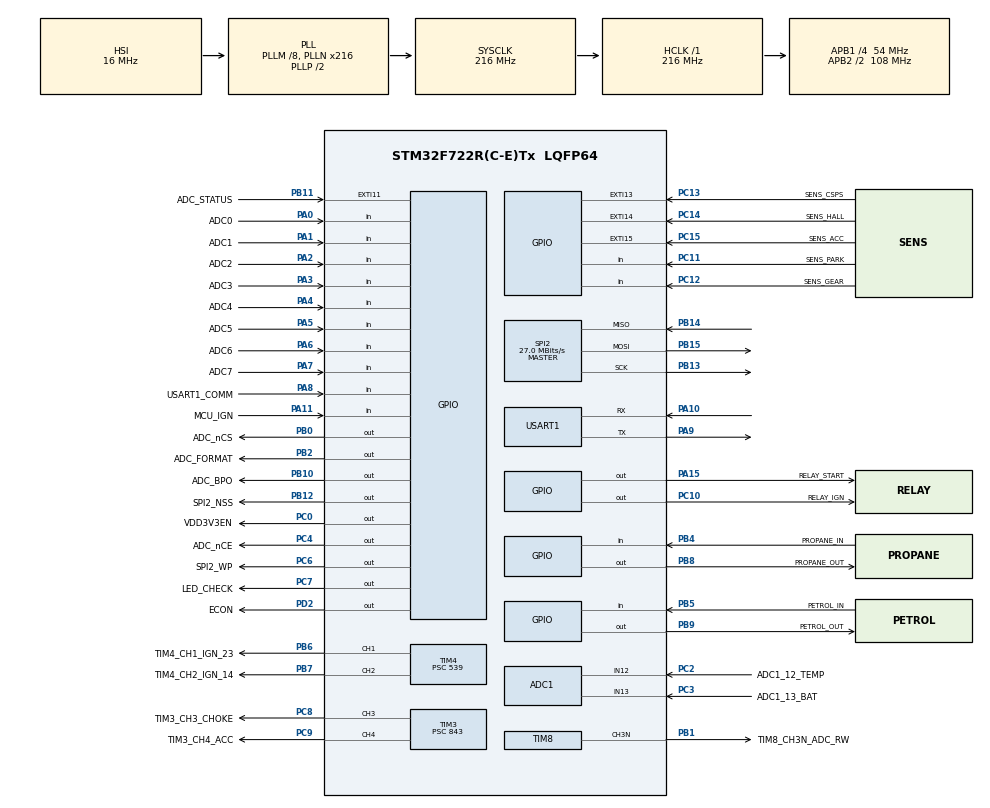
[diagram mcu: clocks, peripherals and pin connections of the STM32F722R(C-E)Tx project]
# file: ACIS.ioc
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ADC1.Channel-0\#ChannelRegularConversion=ADC_CHANNEL_12
ADC1.Channel-1\#ChannelRegularConversion=ADC_CHANNEL_13
ADC1.DMAContinuousRequests=ENABLE
ADC1.DataAlign=ADC_DATAALIGN_LEFT
ADC1.ExternalTrigConv=ADC_EXTERNALTRIGCONV_T8_TRGO
ADC1.NbrOfConversion=2
ADC1.NbrOfConversionFlag=1
ADC1.Rank-0\#ChannelRegularConversion=1
ADC1.Rank-1\#ChannelRegularConversion=2
ADC1.SamplingTime-0\#ChannelRegularConversion=ADC_SAMPLETIME_3CYCLES
ADC1.SamplingTime-1\#ChannelRegularConversion=ADC_SAMPLETIME_3CYCLES
ADC1.ScanConvMode=ADC_SCAN_ENABLE
ADC1.master=1
CORTEX_M7.ART_ACCLERATOR_ENABLE=1
CORTEX_M7.CPU_DCache=Enabled
CORTEX_M7.CPU_ICache=Enabled
CORTEX_M7.FlashInterface=TCM_Enabled
CORTEX_M7.PREFETCH_ENABLE=1
CRC.CRCLength=CRC_POLYLENGTH_16B
CRC.DefaultInitValueUse=DEFAULT_INIT_VALUE_DISABLE
CRC.DefaultPolynomialUse=DEFAULT_POLYNOMIAL_DISABLE
CRC.InputDataInversionMode=CRC_INPUTDATA_INVERSION_BYTE
CRC.OutputDataInversionMode=CRC_OUTPUTDATA_INVERSION_ENABLE
Dma.ADC1.2.Direction=DMA_PERIPH_TO_MEMORY
Dma.ADC1.2.FIFOMode=DMA_FIFOMODE_DISABLE
Dma.ADC1.2.Instance=DMA2_Stream0
Dma.ADC1.2.MemDataAlignment=DMA_MDATAALIGN_HALFWORD
Dma.ADC1.2.MemInc=DMA_MINC_ENABLE
Dma.ADC1.2.Mode=DMA_CIRCULAR
Dma.ADC1.2.PeriphDataAlignment=DMA_PDATAALIGN_HALFWORD
Dma.ADC1.2.PeriphInc=DMA_PINC_DISABLE
Dma.ADC1.2.Priority=DMA_PRIORITY_LOW
Dma.Request0=USART1_RX
Dma.Request1=USART1_TX
Dma.Request2=ADC1
Dma.Request3=TIM7_UP
Dma.Request4=SPI2_TX
Dma.Request5=SPI2_RX
Dma.SPI2_RX.5.Direction=DMA_PERIPH_TO_MEMORY
Dma.SPI2_RX.5.FIFOMode=DMA_FIFOMODE_DISABLE
Dma.SPI2_RX.5.Instance=DMA1_Stream3
Dma.SPI2_RX.5.MemDataAlignment=DMA_MDATAALIGN_BYTE
Dma.SPI2_RX.5.MemInc=DMA_MINC_ENABLE
Dma.SPI2_RX.5.Mode=DMA_NORMAL
Dma.SPI2_RX.5.PeriphDataAlignment=DMA_PDATAALIGN_BYTE
Dma.SPI2_RX.5.PeriphInc=DMA_PINC_DISABLE
Dma.SPI2_RX.5.Priority=DMA_PRIORITY_LOW
Dma.SPI2_TX.4.Direction=DMA_MEMORY_TO_PERIPH
Dma.SPI2_TX.4.FIFOMode=DMA_FIFOMODE_DISABLE
Dma.SPI2_TX.4.Instance=DMA1_Stream4
Dma.SPI2_TX.4.MemDataAlignment=DMA_MDATAALIGN_BYTE
Dma.SPI2_TX.4.MemInc=DMA_MINC_ENABLE
Dma.SPI2_TX.4.Mode=DMA_NORMAL
Dma.SPI2_TX.4.PeriphDataAlignment=DMA_PDATAALIGN_BYTE
Dma.SPI2_TX.4.PeriphInc=DMA_PINC_DISABLE
Dma.SPI2_TX.4.Priority=DMA_PRIORITY_LOW
Dma.TIM7_UP.3.Direction=DMA_PERIPH_TO_MEMORY
Dma.TIM7_UP.3.FIFOMode=DMA_FIFOMODE_DISABLE
Dma.TIM7_UP.3.Instance=DMA1_Stream2
Dma.TIM7_UP.3.MemDataAlignment=DMA_MDATAALIGN_BYTE
Dma.TIM7_UP.3.MemInc=DMA_MINC_ENABLE
Dma.TIM7_UP.3.Mode=DMA_CIRCULAR
Dma.TIM7_UP.3.PeriphDataAlignment=DMA_PDATAALIGN_BYTE
Dma.TIM7_UP.3.PeriphInc=DMA_PINC_DISABLE
Dma.TIM7_UP.3.Priority=DMA_PRIORITY_LOW
Dma.USART1_RX.0.Direction=DMA_PERIPH_TO_MEMORY
Dma.USART1_RX.0.FIFOMode=DMA_FIFOMODE_DISABLE
Dma.USART1_RX.0.Instance=DMA2_Stream2
Dma.USART1_RX.0.MemDataAlignment=DMA_MDATAALIGN_BYTE
Dma.USART1_RX.0.MemInc=DMA_MINC_ENABLE
Dma.USART1_RX.0.Mode=DMA_NORMAL
Dma.USART1_RX.0.PeriphDataAlignment=DMA_PDATAALIGN_BYTE
Dma.USART1_RX.0.PeriphInc=DMA_PINC_DISABLE
Dma.USART1_RX.0.Priority=DMA_PRIORITY_LOW
Dma.USART1_TX.1.Direction=DMA_MEMORY_TO_PERIPH
Dma.USART1_TX.1.FIFOMode=DMA_FIFOMODE_DISABLE
Dma.USART1_TX.1.Instance=DMA2_Stream7
Dma.USART1_TX.1.MemDataAlignment=DMA_MDATAALIGN_BYTE
Dma.USART1_TX.1.MemInc=DMA_MINC_ENABLE
Dma.USART1_TX.1.Mode=DMA_NORMAL
Dma.USART1_TX.1.PeriphDataAlignment=DMA_PDATAALIGN_BYTE
Dma.USART1_TX.1.PeriphInc=DMA_PINC_DISABLE
Dma.USART1_TX.1.Priority=DMA_PRIORITY_LOW
Mcu.Family=STM32F7
Mcu.Name=STM32F722R(C-E)Tx
Mcu.Package=LQFP64
NVIC.DMA1_Stream2_IRQn=true\:0\:0\:false\:false\:true\:false\:true
NVIC.DMA1_Stream3_IRQn=true\:0\:0\:false\:false\:true\:false\:true
NVIC.DMA1_Stream4_IRQn=true\:0\:0\:false\:false\:true\:false\:true
NVIC.DMA2_Stream0_IRQn=true\:0\:0\:false\:false\:true\:false\:true
NVIC.DMA2_Stream2_IRQn=true\:0\:0\:false\:false\:true\:false\:true
NVIC.DMA2_Stream7_IRQn=true\:0\:0\:false\:false\:true\:false\:true
NVIC.EXTI15_10_IRQn=true\:0\:0\:false\:false\:true\:true\:true
NVIC.PriorityGroup=NVIC_PRIORITYGROUP_4
NVIC.SPI2_IRQn=true\:0\:0\:false\:false\:true\:true\:true
NVIC.TIM7_IRQn=true\:0\:0\:false\:false\:true\:true\:true
NVIC.USART1_IRQn=true\:0\:0\:false\:false\:true\:true\:true
PA0-WKUP.GPIO_Label=ADC0
PA0-WKUP.GPIO_PuPd=GPIO_PULLDOWN
PA0-WKUP.Signal=GPIO_Input
PA1.GPIO_Label=ADC1
PA1.GPIO_PuPd=GPIO_PULLDOWN
PA1.Signal=GPIO_Input
PA10.GPIO_PuPd=GPIO_PULLUP
PA10.Mode=Asynchronous
PA10.Signal=USART1_RX
PA11.GPIO_Label=MCU_IGN
PA11.Signal=GPIO_Input
PA13.Mode=Trace_Asynchronous_SW
PA13.Signal=SYS_JTMS-SWDIO
PA14.Mode=Trace_Asynchronous_SW
PA14.Signal=SYS_JTCK-SWCLK
PA15.GPIO_Label=RELAY_START
PA15.Signal=GPIO_Output
PA2.GPIO_Label=ADC2
PA2.GPIO_PuPd=GPIO_PULLDOWN
PA2.Signal=GPIO_Input
PA3.GPIO_Label=ADC3
PA3.GPIO_PuPd=GPIO_PULLDOWN
PA3.Signal=GPIO_Input
PA4.GPIO_Label=ADC4
PA4.GPIO_PuPd=GPIO_PULLDOWN
PA4.Signal=GPIO_Input
PA5.GPIO_Label=ADC5
PA5.GPIO_PuPd=GPIO_PULLDOWN
PA5.Signal=GPIO_Input
PA6.GPIO_Label=ADC6
PA6.GPIO_PuPd=GPIO_PULLDOWN
PA6.Signal=GPIO_Input
PA7.GPIO_Label=ADC7
PA7.GPIO_PuPd=GPIO_PULLDOWN
PA7.Signal=GPIO_Input
PA8.GPIO_Label=USART1_COMM
PA8.Signal=GPIO_Input
PA9.GPIO_PuPd=GPIO_PULLUP
PA9.Mode=Asynchronous
PA9.Signal=USART1_TX
PB0.GPIO_Label=ADC_nCS
PB0.PinState=GPIO_PIN_SET
PB0.Signal=GPIO_Output
PB1.GPIO_Label=TIM8_CH3N_ADC_RW
PB1.GPIO_PuPd=GPIO_NOPULL
PB1.GPIO_Speed=GPIO_SPEED_FREQ_VERY_HIGH
PB1.Mode=PWM Generation3 CH3N
PB1.Signal=TIM8_CH3N
PB10.GPIO_Label=ADC_BPO
PB10.Signal=GPIO_Output
PB11.GPIO_Label=ADC_STATUS
PB11.GPIO_ModeDefaultEXTI=GPIO_MODE_IT_FALLING
PB11.GPIO_PuPd=GPIO_NOPULL
PB11.Signal=GPXTI11
PB12.GPIO_Label=SPI2_NSS
PB12.GPIO_Speed=GPIO_SPEED_FREQ_VERY_HIGH
PB12.Signal=GPIO_Output
PB13.GPIO_PuPd=GPIO_PULLUP
PB13.Mode=Full_Duplex_Master
PB13.Signal=SPI2_SCK
PB14.GPIO_PuPd=GPIO_PULLUP
PB14.Mode=Full_Duplex_Master
PB14.Signal=SPI2_MISO
PB15.GPIO_PuPd=GPIO_PULLUP
PB15.Mode=Full_Duplex_Master
PB15.Signal=SPI2_MOSI
PB2.GPIO_Label=ADC_FORMAT
PB2.Signal=GPIO_Output
PB3.Mode=Trace_Asynchronous_SW
PB3.Signal=SYS_JTDO-SWO
PB4.GPIO_Label=PROPANE_IN
PB4.Signal=GPIO_Input
PB5.GPIO_Label=PETROL_IN
PB5.Signal=GPIO_Input
PB6.GPIO_Label=TIM4_CH1_IGN_23
PB6.GPIO_PuPd=GPIO_NOPULL
PB6.GPIO_Speed=GPIO_SPEED_FREQ_VERY_HIGH
PB6.Signal=S_TIM4_CH1
PB7.GPIO_Label=TIM4_CH2_IGN_14
PB7.GPIO_PuPd=GPIO_NOPULL
PB7.GPIO_Speed=GPIO_SPEED_FREQ_VERY_HIGH
PB7.Signal=S_TIM4_CH2
PB8.GPIO_Label=PROPANE_OUT
PB8.Signal=GPIO_Output
PB9.GPIO_Label=PETROL_OUT
PB9.Signal=GPIO_Output
PC0.GPIO_Label=VDD3V3EN
PC0.Signal=GPIO_Output
PC10.GPIO_Label=RELAY_IGN
PC10.Signal=GPIO_Output
PC11.GPIO_Label=SENS_PARK
PC11.Signal=GPIO_Input
PC12.GPIO_Label=SENS_GEAR
PC12.Signal=GPIO_Input
PC13.GPIO_Label=SENS_CSPS
PC13.GPIO_ModeDefaultEXTI=GPIO_MODE_IT_RISING_FALLING
PC13.Signal=GPXTI13
PC14-OSC32_IN.GPIO_Label=SENS_HALL
PC14-OSC32_IN.GPIO_ModeDefaultEXTI=GPIO_MODE_IT_RISING
PC14-OSC32_IN.Signal=GPXTI14
PC15-OSC32_OUT.GPIO_Label=SENS_ACC
PC15-OSC32_OUT.Signal=GPXTI15
PC2.GPIO_Label=ADC1_12_TEMP
PC2.Signal=ADCx_IN12
PC3.GPIO_Label=ADC1_13_BAT
PC3.Signal=ADCx_IN13
PC4.GPIO_Label=ADC_nCE
PC4.PinState=GPIO_PIN_SET
PC4.Signal=GPIO_Output
PC6.GPIO_Label=SPI2_WP
PC6.GPIO_Speed=GPIO_SPEED_FREQ_VERY_HIGH
PC6.Signal=GPIO_Output
PC7.GPIO_Label=LED_CHECK
PC7.PinState=GPIO_PIN_SET
PC7.Signal=GPIO_Output
PC8.GPIO_Label=TIM3_CH3_CHOKE
PC8.GPIO_PuPd=GPIO_NOPULL
PC8.GPIO_Speed=GPIO_SPEED_FREQ_VERY_HIGH
PC8.Signal=S_TIM3_CH3
PC9.GPIO_Label=TIM3_CH4_ACC
PC9.GPIO_PuPd=GPIO_NOPULL
PC9.GPIO_Speed=GPIO_SPEED_FREQ_VERY_HIGH
PC9.Signal=S_TIM3_CH4
PD2.GPIO_Label=ECON
PD2.Signal=GPIO_Output
ProjectManager.HeapSize=0x200
ProjectManager.StackSize=0x400
ProjectManager.TargetToolchain=STM32CubeIDE
RCC.AHBFreq_Value=216000000
RCC.APB1CLKDivider=RCC_HCLK_DIV4
RCC.APB1Freq_Value=54000000
RCC.APB1TimFreq_Value=108000000
RCC.APB2CLKDivider=RCC_HCLK_DIV2
RCC.APB2Freq_Value=108000000
RCC.APB2TimFreq_Value=216000000
RCC.CortexFreq_Value=216000000
RCC.HCLKFreq_Value=216000000
RCC.HSE_VALUE=25000000
RCC.HSI_VALUE=16000000
RCC.LSE_VALUE=32768
RCC.PLLM=8
RCC.PLLN=216
RCC.PLLQ=9
RCC.SYSCLKFreq_VALUE=216000000
RCC.SYSCLKSource=RCC_SYSCLKSOURCE_PLLCLK
RCC.USBFreq_Value=48000000
RCC.VCOOutputFreq_Value=432000000
SH.ADCx_IN12.0=ADC1_IN12,IN12
SH.ADCx_IN13.0=ADC1_IN13,IN13
SH.S_TIM3_CH3.0=TIM3_CH3,PWM Generation3 CH3
SH.S_TIM3_CH4.0=TIM3_CH4,PWM Generation4 CH4
SH.S_TIM4_CH1.0=TIM4_CH1,PWM Generation1 CH1
SH.S_TIM4_CH2.0=TIM4_CH2,PWM Generation2 CH2
SPI2.CalculateBaudRate=27.0 MBits/s
SPI2.DataSize=SPI_DATASIZE_8BIT
SPI2.Direction=SPI_DIRECTION_2LINES
SPI2.Mode=SPI_MODE_MASTER
SPI2.VirtualType=VM_MASTER
TIM3.Channel-PWM\ Generation3\ CH3=TIM_CHANNEL_3
TIM3.Channel-PWM\ Generation4\ CH4=TIM_CHANNEL_4
TIM3.Period=5119
TIM3.Prescaler=843
TIM3.Pulse-PWM\ Generation3\ CH3=256
TIM3.Pulse-PWM\ Generation4\ CH4=256
TIM4.Channel-PWM\ Generation1\ CH1=TIM_CHANNEL_1
TIM4.Channel-PWM\ Generation2\ CH2=TIM_CHANNEL_2
TIM4.OCMode_PWM-PWM\ Generation2\ CH2=TIM_OCMODE_PWM1
TIM4.Period=19
TIM4.Prescaler=539
TIM4.Pulse-PWM\ Generation1\ CH1=15
TIM4.Pulse-PWM\ Generation2\ CH2=15
TIM7.Period=53
TIM8.Channel-PWM\ Generation3\ CH3N=TIM_CHANNEL_3
TIM8.OCNIdleState_3=TIM_OCNIDLESTATE_SET
TIM8.OCNPolarity_3=TIM_OCNPOLARITY_LOW
TIM8.Period=99
TIM8.Prescaler=107
TIM8.Pulse-PWM\ Generation3\ CH3N=1
TIM8.TIM_MasterOutputTrigger=TIM_TRGO_UPDATE
USART1.AutoBaudRateEnableParam=UART_ADVFEATURE_AUTOBAUDRATE_ENABLE
USART1.OverSampling=UART_OVERSAMPLING_16
USART1.VirtualMode-Asynchronous=VM_ASYNC
VP_CRC_VS_CRC.Mode=CRC_Activate
VP_IWDG_VS_IWDG.Mode=IWDG_Activate
VP_RNG_VS_RNG.Mode=RNG_Activate
VP_TIM4_VS_ClockSourceINT.Mode=Internal
VP_TIM4_VS_OPM.Mode=OPM_bit
VP_TIM7_VS_ClockSourceINT.Mode=Enable_Timer
VP_TIM7_VS_OPM.Mode=OPM_bit
board=custom

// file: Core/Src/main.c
#include "main.h"
#include "delay.h"
#include "acis.h"
#include "csps.h"
#include "map.h"
#include "crc.h"
#include "xCommand.h"
#include "sst25vf032b.h"

#define IS_DEBUGGER_ATTACHED() (DBGMCU->CR & 0x07)

#define ADC_BUF_SIZE 256
uint16_t ADC_BUF[ADC_BUF_SIZE] __attribute__((aligned(32)));

ADC_HandleTypeDef hadc1;
DMA_HandleTypeDef hdma_adc1;

CRC_HandleTypeDef hcrc;

IWDG_HandleTypeDef hiwdg;

RNG_HandleTypeDef hrng;

SPI_HandleTypeDef hspi2;
DMA_HandleTypeDef hdma_spi2_tx;
DMA_HandleTypeDef hdma_spi2_rx;

TIM_HandleTypeDef htim3;
TIM_HandleTypeDef htim4;
TIM_HandleTypeDef htim7;
TIM_HandleTypeDef htim8;
DMA_HandleTypeDef hdma_tim7_up;

UART_HandleTypeDef huart1;
DMA_HandleTypeDef hdma_usart1_rx;
DMA_HandleTypeDef hdma_usart1_tx;

void SystemClock_Config(void);
static void MX_GPIO_Init(void);
static void MX_DMA_Init(void);
static void MX_IWDG_Init(void);
static void MX_USART1_UART_Init(void);
static void MX_SPI2_Init(void);
static void MX_ADC1_Init(void);
static void MX_TIM3_Init(void);
static void MX_TIM4_Init(void);
static void MX_TIM8_Init(void);
static void MX_TIM7_Init(void);
static void MX_CRC_Init(void);
static void MX_RNG_Init(void);
static void UpdateIWDG(void);
static void UpdateDebugger(void);

inline void HAL_GPIO_EXTI_Callback(uint16_t GPIO_Pin)
{
  switch(GPIO_Pin)
  {
    case SENS_CSPS_Pin :
      csps_exti();
      break;
    case SENS_HALL_Pin :
      acis_hall_exti();
      break;
    case ADC_STATUS_Pin :
      HAL_TIM_Base_Start_IT(&htim7);
      break;
    default:
      break;
  }
}

inline void HAL_TIM_PeriodElapsedCallback(TIM_HandleTypeDef *htim)
{
  static uint16_t ms_tim = 0;
  if(htim == &htim4)
  {
    acis_loop_irq();
    if(++ms_tim >= 500)
    {
      csps_loop();
      ms_tim = 0;
    }
  }
  else if(htim == &htim7)
  {
    map_adc_read();
  }
}

void HAL_UART_TxCpltCallback(UART_HandleTypeDef *huart)
{
  xDmaTxIrqHandler(huart);
}

void HAL_UART_ErrorCallback(UART_HandleTypeDef *huart)
{
  xDmaErIrqHandler(huart);
}

void HAL_SPI_ErrorCallback(SPI_HandleTypeDef * hspi)
{
  if(hspi == &hspi2)
  {
    SST25_ErrorCallback(hspi);
  }
}

void HAL_SPI_TxCpltCallback(SPI_HandleTypeDef * hspi)
{
  if(hspi == &hspi2)
  {
    SST25_TxCpltCallback(hspi);
  }
}

void HAL_SPI_RxCpltCallback(SPI_HandleTypeDef * hspi)
{
  if(hspi == &hspi2)
  {
    SST25_RxCpltCallback(hspi);
  }
}
void HAL_SPI_TxRxCpltCallback(SPI_HandleTypeDef * hspi)
{
  if(hspi == &hspi2)
  {
    SST25_TxRxCpltCallback(hspi);
  }
}

void HAL_ADC_ConvHalfCpltCallback(ADC_HandleTypeDef * hadc)
{
  if(hadc == &hadc1)
  {
    SCB_InvalidateDCache_by_Addr((uint32_t*)&ADC_BUF[0], ADC_BUF_SIZE);
    acis_adc_irq(&ADC_BUF[0], ADC_BUF_SIZE / 2);
  }
}

void HAL_ADC_ConvCpltCallback(ADC_HandleTypeDef * hadc)
{
  if(hadc == &hadc1)
  {
    SCB_InvalidateDCache_by_Addr((uint32_t*)&ADC_BUF[ADC_BUF_SIZE / 2], ADC_BUF_SIZE);
    acis_adc_irq(&ADC_BUF[ADC_BUF_SIZE / 2], ADC_BUF_SIZE / 2);
  }
}

int main(void)
{
  SCB_EnableICache();

  SCB_EnableDCache();

  HAL_Init();

  SystemClock_Config();

  MX_GPIO_Init();
  MX_DMA_Init();
  //MX_IWDG_Init();
  MX_USART1_UART_Init();  //Control Communication
  MX_SPI2_Init(); //SPI Flash
  MX_ADC1_Init(); //Temperature and battery sensor
  MX_TIM3_Init(); //Servo PWM
  MX_TIM4_Init(); //ACIS common workout IT
  MX_TIM7_Init(); //Wait timer for ADC670
  MX_TIM8_Init(); //ADCs trigger strobe
  MX_CRC_Init();
  MX_RNG_Init();
  DelayInit();

  SST25_Init(&hspi2);

  CRC16_RegisterHardware(&hcrc);

  xFifosInit();
  xGetterInit();

  SCB_CleanDCache_by_Addr((uint32_t*)&ADC_BUF[0], ADC_BUF_SIZE*2);
  HAL_ADC_Start_DMA(&hadc1, (uint32_t*)ADC_BUF, ADC_BUF_SIZE);

  map_init();
  acis_init();

  HAL_TIM_Base_Start(&htim8);

  while (1)
  {
    UpdateIWDG();
    UpdateDebugger();
    xGetterLoop();
    acis_loop();
    acis_deinitIfNeed();
  }
}

static inline void UpdateIWDG(void)
{
  static uint32_t delay_old = 0;
  uint32_t delay = Delay_Tick;
  if(DelayDiff(delay, delay_old) > 1000000)
  {
    delay_old = delay;
    HAL_IWDG_Refresh(&hiwdg);
  }
}

static inline void UpdateDebugger(void)
{
  static uint8_t was_attached = 0;
  uint8_t attached = IS_DEBUGGER_ATTACHED();
  if(was_attached != attached)
  {
    was_attached = attached;
    if(attached)
    {
      __HAL_DBGMCU_FREEZE_IWDG();
      __HAL_DBGMCU_FREEZE_TIM4();
      __HAL_DBGMCU_FREEZE_TIM5();
      __HAL_DBGMCU_FREEZE_TIM7();
      __HAL_DBGMCU_FREEZE_TIM8();
    }
    else
    {
      __HAL_DBGMCU_UNFREEZE_IWDG();
      __HAL_DBGMCU_UNFREEZE_TIM4();
      __HAL_DBGMCU_UNFREEZE_TIM5();
      __HAL_DBGMCU_UNFREEZE_TIM7();
      __HAL_DBGMCU_UNFREEZE_TIM8();
    }
  }
}

void SystemClock_Config(void)
{
  RCC_OscInitTypeDef RCC_OscInitStruct = {0};
  RCC_ClkInitTypeDef RCC_ClkInitStruct = {0};
  RCC_PeriphCLKInitTypeDef PeriphClkInitStruct = {0};

  /** Configure the main internal regulator output voltage
  */
  __HAL_RCC_PWR_CLK_ENABLE();
  __HAL_PWR_VOLTAGESCALING_CONFIG(PWR_REGULATOR_VOLTAGE_SCALE1);
  /** Initializes the RCC Oscillators according to the specified parameters
  * in the RCC_OscInitTypeDef structure.
  */
  RCC_OscInitStruct.OscillatorType = RCC_OSCILLATORTYPE_HSI|RCC_OSCILLATORTYPE_LSI;
  RCC_OscInitStruct.HSIState = RCC_HSI_ON;
  RCC_OscInitStruct.HSICalibrationValue = 7;
  RCC_OscInitStruct.LSIState = RCC_LSI_ON;
  RCC_OscInitStruct.PLL.PLLState = RCC_PLL_ON;
  RCC_OscInitStruct.PLL.PLLSource = RCC_PLLSOURCE_HSI;
  RCC_OscInitStruct.PLL.PLLM = 8;
  RCC_OscInitStruct.PLL.PLLN = 216;
  RCC_OscInitStruct.PLL.PLLP = RCC_PLLP_DIV2;
  RCC_OscInitStruct.PLL.PLLQ = 9;
  if (HAL_RCC_OscConfig(&RCC_OscInitStruct) != HAL_OK)
  {
    Error_Handler();
  }
  /** Activate the Over-Drive mode
  */
  if (HAL_PWREx_EnableOverDrive() != HAL_OK)
  {
    Error_Handler();
  }
  /** Initializes the CPU, AHB and APB buses clocks
  */
  RCC_ClkInitStruct.ClockType = RCC_CLOCKTYPE_HCLK|RCC_CLOCKTYPE_SYSCLK
                              |RCC_CLOCKTYPE_PCLK1|RCC_CLOCKTYPE_PCLK2;
  RCC_ClkInitStruct.SYSCLKSource = RCC_SYSCLKSOURCE_PLLCLK;
  RCC_ClkInitStruct.AHBCLKDivider = RCC_SYSCLK_DIV1;
  RCC_ClkInitStruct.APB1CLKDivider = RCC_HCLK_DIV4;
  RCC_ClkInitStruct.APB2CLKDivider = RCC_HCLK_DIV2;

  if (HAL_RCC_ClockConfig(&RCC_ClkInitStruct, FLASH_LATENCY_7) != HAL_OK)
  {
    Error_Handler();
  }
  PeriphClkInitStruct.PeriphClockSelection = RCC_PERIPHCLK_USART1|RCC_PERIPHCLK_CLK48;
  PeriphClkInitStruct.Usart1ClockSelection = RCC_USART1CLKSOURCE_PCLK2;
  PeriphClkInitStruct.Clk48ClockSelection = RCC_CLK48SOURCE_PLL;
  if (HAL_RCCEx_PeriphCLKConfig(&PeriphClkInitStruct) != HAL_OK)
  {
    Error_Handler();
  }
}

static void MX_ADC1_Init(void)
{

  ADC_ChannelConfTypeDef sConfig = {0};

  /** Configure the global features of the ADC (Clock, Resolution, Data Alignment and number of conversion)
  */
  hadc1.Instance = ADC1;
  hadc1.Init.ClockPrescaler = ADC_CLOCK_SYNC_PCLK_DIV4;
  hadc1.Init.Resolution = ADC_RESOLUTION_12B;
  hadc1.Init.ScanConvMode = ADC_SCAN_ENABLE;
  hadc1.Init.ContinuousConvMode = DISABLE;
  hadc1.Init.DiscontinuousConvMode = DISABLE;
  hadc1.Init.ExternalTrigConvEdge = ADC_EXTERNALTRIGCONVEDGE_RISING;
  hadc1.Init.ExternalTrigConv = ADC_EXTERNALTRIGCONV_T8_TRGO;
  hadc1.Init.DataAlign = ADC_DATAALIGN_LEFT;
  hadc1.Init.NbrOfConversion = 2;
  hadc1.Init.DMAContinuousRequests = ENABLE;
  hadc1.Init.EOCSelection = ADC_EOC_SEQ_CONV;
  if (HAL_ADC_Init(&hadc1) != HAL_OK)
  {
    Error_Handler();
  }
  /** Configure for the selected ADC regular channel its corresponding rank in the sequencer and its sample time.
  */
  sConfig.Channel = ADC_CHANNEL_12;
  sConfig.Rank = ADC_REGULAR_RANK_1;
  sConfig.SamplingTime = ADC_SAMPLETIME_56CYCLES;
  if (HAL_ADC_ConfigChannel(&hadc1, &sConfig) != HAL_OK)
  {
    Error_Handler();
  }
  /** Configure for the selected ADC regular channel its corresponding rank in the sequencer and its sample time.
  */
  sConfig.Channel = ADC_CHANNEL_13;
  sConfig.Rank = ADC_REGULAR_RANK_2;
  if (HAL_ADC_ConfigChannel(&hadc1, &sConfig) != HAL_OK)
  {
    Error_Handler();
  }
  /** Configure for the selected ADC regular channel its corresponding rank in the sequencer and its sample time.
  */
  /*
  sConfig.Channel = ADC_CHANNEL_1;
  sConfig.Rank = ADC_REGULAR_RANK_3;
  if (HAL_ADC_ConfigChannel(&hadc1, &sConfig) != HAL_OK)
  {
    Error_Handler();
  }
  */

}

static void MX_CRC_Init(void)
{

  hcrc.Instance = CRC;
  hcrc.Init.DefaultPolynomialUse = DEFAULT_POLYNOMIAL_DISABLE;
  hcrc.Init.DefaultInitValueUse = DEFAULT_INIT_VALUE_DISABLE;
  hcrc.Init.GeneratingPolynomial = 0x8005;
  hcrc.Init.CRCLength = CRC_POLYLENGTH_16B;
  hcrc.Init.InitValue = 0xFFFF;
  hcrc.Init.InputDataInversionMode = CRC_INPUTDATA_INVERSION_BYTE;
  hcrc.Init.OutputDataInversionMode = CRC_OUTPUTDATA_INVERSION_ENABLE;
  hcrc.InputDataFormat = CRC_INPUTDATA_FORMAT_BYTES;
  if (HAL_CRC_Init(&hcrc) != HAL_OK)
  {
    Error_Handler();
  }

}

static void MX_IWDG_Init(void)
{

  hiwdg.Instance = IWDG;
  hiwdg.Init.Prescaler = IWDG_PRESCALER_256;
  hiwdg.Init.Window = 256;
  hiwdg.Init.Reload = 256;
  if (HAL_IWDG_Init(&hiwdg) != HAL_OK)
  {
    Error_Handler();
  }

}

static void MX_RNG_Init(void)
{

  hrng.Instance = RNG;
  if (HAL_RNG_Init(&hrng) != HAL_OK)
  {
    Error_Handler();
  }

}

static void MX_SPI2_Init(void)
{

  /* SPI2 parameter configuration*/
  hspi2.Instance = SPI2;
  hspi2.Init.Mode = SPI_MODE_MASTER;
  hspi2.Init.Direction = SPI_DIRECTION_2LINES;
  hspi2.Init.DataSize = SPI_DATASIZE_8BIT;
  hspi2.Init.CLKPolarity = SPI_POLARITY_LOW;
  hspi2.Init.CLKPhase = SPI_PHASE_1EDGE;
  hspi2.Init.NSS = SPI_NSS_SOFT;
  hspi2.Init.BaudRatePrescaler = SPI_BAUDRATEPRESCALER_2;
  hspi2.Init.FirstBit = SPI_FIRSTBIT_MSB;
  hspi2.Init.TIMode = SPI_TIMODE_DISABLE;
  hspi2.Init.CRCCalculation = SPI_CRCCALCULATION_DISABLE;
  hspi2.Init.CRCPolynomial = 7;
  hspi2.Init.CRCLength = SPI_CRC_LENGTH_DATASIZE;
  hspi2.Init.NSSPMode = SPI_NSS_PULSE_ENABLE;
  if (HAL_SPI_Init(&hspi2) != HAL_OK)
  {
    Error_Handler();
  }

}

static void MX_TIM3_Init(void)
{

  TIM_MasterConfigTypeDef sMasterConfig = {0};
  TIM_OC_InitTypeDef sConfigOC = {0};

  htim3.Instance = TIM3;
  htim3.Init.Prescaler = (HAL_RCC_GetPCLK1Freq() * 2 / 50 / 5120) - 1; //This is to set prescaler to 1 MHz
  htim3.Init.CounterMode = TIM_COUNTERMODE_UP;
  htim3.Init.Period = 5119;
  htim3.Init.ClockDivision = TIM_CLOCKDIVISION_DIV1;
  htim3.Init.AutoReloadPreload = TIM_AUTORELOAD_PRELOAD_DISABLE;
  if (HAL_TIM_PWM_Init(&htim3) != HAL_OK)
  {
    Error_Handler();
  }
  sMasterConfig.MasterOutputTrigger = TIM_TRGO_RESET;
  sMasterConfig.MasterSlaveMode = TIM_MASTERSLAVEMODE_DISABLE;
  if (HAL_TIMEx_MasterConfigSynchronization(&htim3, &sMasterConfig) != HAL_OK)
  {
    Error_Handler();
  }
  sConfigOC.OCMode = TIM_OCMODE_PWM1;
  sConfigOC.Pulse = 256;
  sConfigOC.OCPolarity = TIM_OCPOLARITY_HIGH;
  sConfigOC.OCFastMode = TIM_OCFAST_DISABLE;
  if (HAL_TIM_PWM_ConfigChannel(&htim3, &sConfigOC, TIM_CHANNEL_3) != HAL_OK)
  {
    Error_Handler();
  }
  if (HAL_TIM_PWM_ConfigChannel(&htim3, &sConfigOC, TIM_CHANNEL_4) != HAL_OK)
  {
    Error_Handler();
  }
  HAL_TIM_MspPostInit(&htim3);

}

static void MX_TIM4_Init(void)
{

  TIM_ClockConfigTypeDef sClockSourceConfig = {0};

  htim4.Instance = TIM4;
  htim4.Init.Prescaler = (HAL_RCC_GetPCLK1Freq() * 2 / 1000000) - 1; //This is to set prescaler to 1 MHz
  htim4.Init.CounterMode = TIM_COUNTERMODE_UP;
  htim4.Init.Period = 14;
  htim4.Init.ClockDivision = TIM_CLOCKDIVISION_DIV1;
  htim4.Init.AutoReloadPreload = TIM_AUTORELOAD_PRELOAD_DISABLE;
  if (HAL_TIM_Base_Init(&htim4) != HAL_OK)
  {
    Error_Handler();
  }
  sClockSourceConfig.ClockSource = TIM_CLOCKSOURCE_INTERNAL;
  if (HAL_TIM_ConfigClockSource(&htim4, &sClockSourceConfig) != HAL_OK)
  {
    Error_Handler();
  }

}

static void MX_TIM7_Init(void)
{

  TIM_MasterConfigTypeDef sMasterConfig = {0};

  htim7.Instance = TIM7;
  htim7.Init.Prescaler = 0;
  htim7.Init.CounterMode = TIM_COUNTERMODE_UP;
  htim7.Init.Period = (HAL_RCC_GetPCLK1Freq() * 2 / 1000000) / 2 - 1; //This is to set period to 2 MHz;
  htim7.Init.AutoReloadPreload = TIM_AUTORELOAD_PRELOAD_DISABLE;
  if (HAL_TIM_Base_Init(&htim7) != HAL_OK)
  {
    Error_Handler();
  }
  if (HAL_TIM_OnePulse_Init(&htim7, TIM_OPMODE_SINGLE) != HAL_OK)
  {
    Error_Handler();
  }
  sMasterConfig.MasterOutputTrigger = TIM_TRGO_UPDATE;
  sMasterConfig.MasterSlaveMode = TIM_MASTERSLAVEMODE_DISABLE;
  if (HAL_TIMEx_MasterConfigSynchronization(&htim7, &sMasterConfig) != HAL_OK)
  {
    Error_Handler();
  }

}

static void MX_TIM8_Init(void)
{

  TIM_MasterConfigTypeDef sMasterConfig = {0};
  TIM_OC_InitTypeDef sConfigOC = {0};
  TIM_BreakDeadTimeConfigTypeDef sBreakDeadTimeConfig = {0};

  htim8.Instance = TIM8;
  htim8.Init.Prescaler = (HAL_RCC_GetPCLK2Freq() * 2 / 1000000) - 1; //This is to set prescaler to 1 MHz
  htim8.Init.CounterMode = TIM_COUNTERMODE_UP;
  htim8.Init.Period = 149;
  htim8.Init.ClockDivision = TIM_CLOCKDIVISION_DIV1;
  htim8.Init.RepetitionCounter = 0;
  htim8.Init.AutoReloadPreload = TIM_AUTORELOAD_PRELOAD_DISABLE;
  if (HAL_TIM_PWM_Init(&htim8) != HAL_OK)
  {
    Error_Handler();
  }
  sMasterConfig.MasterOutputTrigger = TIM_TRGO_UPDATE;
  sMasterConfig.MasterOutputTrigger2 = TIM_TRGO2_RESET;
  sMasterConfig.MasterSlaveMode = TIM_MASTERSLAVEMODE_DISABLE;
  if (HAL_TIMEx_MasterConfigSynchronization(&htim8, &sMasterConfig) != HAL_OK)
  {
    Error_Handler();
  }
  sConfigOC.OCMode = TIM_OCMODE_PWM1;
  sConfigOC.Pulse = 1;
  sConfigOC.OCPolarity = TIM_OCPOLARITY_HIGH;
  sConfigOC.OCNPolarity = TIM_OCNPOLARITY_LOW;
  sConfigOC.OCFastMode = TIM_OCFAST_DISABLE;
  sConfigOC.OCIdleState = TIM_OCIDLESTATE_RESET;
  sConfigOC.OCNIdleState = TIM_OCNIDLESTATE_SET;
  if (HAL_TIM_PWM_ConfigChannel(&htim8, &sConfigOC, TIM_CHANNEL_3) != HAL_OK)
  {
    Error_Handler();
  }
  sBreakDeadTimeConfig.OffStateRunMode = TIM_OSSR_DISABLE;
  sBreakDeadTimeConfig.OffStateIDLEMode = TIM_OSSI_DISABLE;
  sBreakDeadTimeConfig.LockLevel = TIM_LOCKLEVEL_OFF;
  sBreakDeadTimeConfig.DeadTime = 0;
  sBreakDeadTimeConfig.BreakState = TIM_BREAK_DISABLE;
  sBreakDeadTimeConfig.BreakPolarity = TIM_BREAKPOLARITY_HIGH;
  sBreakDeadTimeConfig.BreakFilter = 0;
  sBreakDeadTimeConfig.Break2State = TIM_BREAK2_DISABLE;
  sBreakDeadTimeConfig.Break2Polarity = TIM_BREAK2POLARITY_HIGH;
  sBreakDeadTimeConfig.Break2Filter = 0;
  sBreakDeadTimeConfig.AutomaticOutput = TIM_AUTOMATICOUTPUT_DISABLE;
  if (HAL_TIMEx_ConfigBreakDeadTime(&htim8, &sBreakDeadTimeConfig) != HAL_OK)
  {
    Error_Handler();
  }
  HAL_TIM_MspPostInit(&htim8);

}

static void MX_USART1_UART_Init(void)
{

  huart1.Instance = USART1;
  huart1.Init.BaudRate = 3375000;
  huart1.Init.WordLength = UART_WORDLENGTH_8B;
  huart1.Init.StopBits = UART_STOPBITS_1;
  huart1.Init.Parity = UART_PARITY_NONE;
  huart1.Init.Mode = UART_MODE_TX_RX;
  huart1.Init.HwFlowCtl = UART_HWCONTROL_NONE;
  huart1.Init.OverSampling = UART_OVERSAMPLING_16;
  huart1.Init.OneBitSampling = UART_ONE_BIT_SAMPLE_DISABLE;
  huart1.AdvancedInit.AdvFeatureInit = UART_ADVFEATURE_AUTOBAUDRATE_INIT;
  huart1.AdvancedInit.AutoBaudRateEnable = UART_ADVFEATURE_AUTOBAUDRATE_ENABLE;
  huart1.AdvancedInit.AutoBaudRateMode = UART_ADVFEATURE_AUTOBAUDRATE_ON0X55FRAME;
  if (HAL_UART_Init(&huart1) != HAL_OK)
  {
    Error_Handler();
  }

}

static void MX_DMA_Init(void)
{

  /* DMA controller clock enable */
  __HAL_RCC_DMA2_CLK_ENABLE();
  __HAL_RCC_DMA1_CLK_ENABLE();

  /* DMA interrupt init */
  /* DMA1_Stream2_IRQn interrupt configuration */
  HAL_NVIC_SetPriority(DMA1_Stream2_IRQn, 5, 0); //TIM7_UP
  HAL_NVIC_EnableIRQ(DMA1_Stream2_IRQn);
  /* DMA1_Stream3_IRQn interrupt configuration */
  HAL_NVIC_SetPriority(DMA1_Stream3_IRQn, 15, 0); //SPI2_RX
  HAL_NVIC_EnableIRQ(DMA1_Stream3_IRQn);
  /* DMA1_Stream4_IRQn interrupt configuration */
  HAL_NVIC_SetPriority(DMA1_Stream4_IRQn, 15, 0); //SPI2_TX
  HAL_NVIC_EnableIRQ(DMA1_Stream4_IRQn);
  /* DMA2_Stream0_IRQn interrupt configuration */
  HAL_NVIC_SetPriority(DMA2_Stream0_IRQn, 10, 0); //ADC1
  HAL_NVIC_EnableIRQ(DMA2_Stream0_IRQn);
  /* DMA2_Stream2_IRQn interrupt configuration */
  HAL_NVIC_SetPriority(DMA2_Stream2_IRQn, 8, 0); //USART1_RX
  HAL_NVIC_EnableIRQ(DMA2_Stream2_IRQn);
  /* DMA2_Stream7_IRQn interrupt configuration */
  HAL_NVIC_SetPriority(DMA2_Stream7_IRQn, 8, 0); //USART1_TX
  HAL_NVIC_EnableIRQ(DMA2_Stream7_IRQn);

}

static void MX_GPIO_Init(void)
{
  GPIO_InitTypeDef GPIO_InitStruct = {0};

  /* GPIO Ports Clock Enable */
  __HAL_RCC_GPIOC_CLK_ENABLE();
  __HAL_RCC_GPIOA_CLK_ENABLE();
  __HAL_RCC_GPIOB_CLK_ENABLE();
  __HAL_RCC_GPIOD_CLK_ENABLE();
  __HAL_RCC_GPIOH_CLK_ENABLE();

  /*Configure GPIO pin Output Level */
  HAL_GPIO_WritePin(GPIOC, VDD3V3EN_Pin|SPI2_WP_Pin|RELAY_IGN_Pin, GPIO_PIN_RESET);

  HAL_GPIO_WritePin(GPIOB, IGN_14_Pin|IGN_23_Pin, GPIO_PIN_SET);

  /*Configure GPIO pin Output Level */
  HAL_GPIO_WritePin(GPIOC, ADC_nCE_Pin|LED_CHECK_Pin, GPIO_PIN_SET);

  /*Configure GPIO pin Output Level */
  HAL_GPIO_WritePin(ADC_nCS_GPIO_Port, ADC_nCS_Pin, GPIO_PIN_SET);

  /*Configure GPIO pin Output Level */
  HAL_GPIO_WritePin(GPIOB, ADC_FORMAT_Pin|ADC_BPO_Pin|PROPANE_OUT_Pin
                          |PETROL_OUT_Pin, GPIO_PIN_RESET);

  HAL_GPIO_WritePin(GPIOB, SPI2_NSS_Pin, GPIO_PIN_SET);

  /*Configure GPIO pin Output Level */
  HAL_GPIO_WritePin(RELAY_START_GPIO_Port, RELAY_START_Pin, GPIO_PIN_RESET);
  HAL_GPIO_WritePin(TACHOMETER_GPIO_Port, TACHOMETER_Pin, GPIO_PIN_RESET);

  /*Configure GPIO pin Output Level */
  HAL_GPIO_WritePin(ECON_GPIO_Port, ECON_Pin, GPIO_PIN_RESET);

  /*Configure GPIO pin : SENS_CSPS_Pin */
  GPIO_InitStruct.Pin = SENS_CSPS_Pin;
  GPIO_InitStruct.Mode = GPIO_MODE_IT_RISING_FALLING;
  GPIO_InitStruct.Pull = GPIO_PULLDOWN;
  HAL_GPIO_Init(SENS_CSPS_GPIO_Port, &GPIO_InitStruct);

  /*Configure GPIO pins : SENS_HALL_Pin */
  GPIO_InitStruct.Pin = SENS_HALL_Pin;
  GPIO_InitStruct.Mode = GPIO_MODE_IT_RISING;
  GPIO_InitStruct.Pull = GPIO_NOPULL;
  HAL_GPIO_Init(GPIOC, &GPIO_InitStruct);

  /*Configure GPIO pins : SENS_ACC_Pin */
  GPIO_InitStruct.Pin = SENS_ACC_Pin;
  GPIO_InitStruct.Mode = GPIO_MODE_INPUT;
  GPIO_InitStruct.Pull = GPIO_PULLUP;
  HAL_GPIO_Init(GPIOC, &GPIO_InitStruct);

  /*Configure GPIO pins : VDD3V3EN_Pin ADC_nCE_Pin LED_CHECK_Pin RELAY_IGN_Pin */
  GPIO_InitStruct.Pin = VDD3V3EN_Pin|ADC_nCE_Pin|LED_CHECK_Pin|RELAY_IGN_Pin;
  GPIO_InitStruct.Mode = GPIO_MODE_OUTPUT_PP;
  GPIO_InitStruct.Pull = GPIO_NOPULL;
  GPIO_InitStruct.Speed = GPIO_SPEED_FREQ_LOW;
  HAL_GPIO_Init(GPIOC, &GPIO_InitStruct);

  /*Configure GPIO pins : ADC0_Pin ADC1_Pin ADC2_Pin ADC3_Pin
                           ADC4_Pin ADC5_Pin ADC6_Pin ADC7_Pin */
  GPIO_InitStruct.Pin = ADC0_Pin|ADC1_Pin|ADC2_Pin|ADC3_Pin
                          |ADC4_Pin|ADC5_Pin|ADC6_Pin|ADC7_Pin;
  GPIO_InitStruct.Mode = GPIO_MODE_INPUT;
  GPIO_InitStruct.Pull = GPIO_PULLDOWN;
  //HAL_GPIO_Init(GPIOA, &GPIO_InitStruct);

  /*Configure GPIO pins : ADC_nCS_Pin ADC_FORMAT_Pin ADC_BPO_Pin PROPANE_OUT_Pin
                           PETROL_OUT_Pin */
  GPIO_InitStruct.Pin = ADC_nCS_Pin|ADC_FORMAT_Pin|ADC_BPO_Pin|PROPANE_OUT_Pin
                          |PETROL_OUT_Pin;
  GPIO_InitStruct.Mode = GPIO_MODE_OUTPUT_PP;
  GPIO_InitStruct.Pull = GPIO_NOPULL;
  GPIO_InitStruct.Speed = GPIO_SPEED_FREQ_VERY_HIGH;
  HAL_GPIO_Init(GPIOB, &GPIO_InitStruct);

  /*Configure GPIO pin : ADC_STATUS_Pin */
  GPIO_InitStruct.Pin = ADC_STATUS_Pin;
  GPIO_InitStruct.Mode = GPIO_MODE_IT_FALLING;
  GPIO_InitStruct.Pull = GPIO_PULLDOWN;
  HAL_GPIO_Init(ADC_STATUS_GPIO_Port, &GPIO_InitStruct);

  /*Configure GPIO pin : SPI2_NSS_Pin */
  GPIO_InitStruct.Pin = SPI2_NSS_Pin;
  GPIO_InitStruct.Mode = GPIO_MODE_OUTPUT_PP;
  GPIO_InitStruct.Pull = GPIO_NOPULL;
  GPIO_InitStruct.Speed = GPIO_SPEED_FREQ_VERY_HIGH;
  HAL_GPIO_Init(SPI2_NSS_GPIO_Port, &GPIO_InitStruct);

  /*Configure GPIO pin : SPI2_WP_Pin */
  GPIO_InitStruct.Pin = SPI2_WP_Pin;
  GPIO_InitStruct.Mode = GPIO_MODE_OUTPUT_PP;
  GPIO_InitStruct.Pull = GPIO_NOPULL;
  GPIO_InitStruct.Speed = GPIO_SPEED_FREQ_VERY_HIGH;
  HAL_GPIO_Init(SPI2_WP_GPIO_Port, &GPIO_InitStruct);

  /*Configure GPIO pin : TACHOMETER_Pin */
  GPIO_InitStruct.Pin = TACHOMETER_Pin;
  GPIO_InitStruct.Mode = GPIO_MODE_OUTPUT_PP;
  GPIO_InitStruct.Pull = GPIO_NOPULL;
  GPIO_InitStruct.Speed = GPIO_SPEED_FREQ_VERY_HIGH;
  HAL_GPIO_Init(TACHOMETER_GPIO_Port, &GPIO_InitStruct);

  GPIO_InitStruct.Pin = GPIO_PIN_1;
  GPIO_InitStruct.Mode = GPIO_MODE_ANALOG;
  GPIO_InitStruct.Pull = GPIO_NOPULL;
  HAL_GPIO_Init(GPIOH, &GPIO_InitStruct);

  /*Configure GPIO pins : USART1_COMM_Pin MCU_IGN_Pin */
  GPIO_InitStruct.Pin = USART1_COMM_Pin|MCU_IGN_Pin;
  GPIO_InitStruct.Mode = GPIO_MODE_INPUT;
  GPIO_InitStruct.Pull = GPIO_PULLUP;
  HAL_GPIO_Init(GPIOA, &GPIO_InitStruct);

  /*Configure GPIO pin : RELAY_START_Pin */
  GPIO_InitStruct.Pin = RELAY_START_Pin;
  GPIO_InitStruct.Mode = GPIO_MODE_OUTPUT_PP;
  GPIO_InitStruct.Pull = GPIO_NOPULL;
  GPIO_InitStruct.Speed = GPIO_SPEED_FREQ_LOW;
  HAL_GPIO_Init(RELAY_START_GPIO_Port, &GPIO_InitStruct);

  /*Configure GPIO pins : SENS_PARK_Pin SENS_GEAR_Pin */
  GPIO_InitStruct.Pin = SENS_PARK_Pin|SENS_GEAR_Pin;
  GPIO_InitStruct.Mode = GPIO_MODE_INPUT;
  GPIO_InitStruct.Pull = GPIO_NOPULL;
  HAL_GPIO_Init(GPIOC, &GPIO_InitStruct);

  /*Configure GPIO pin : ECON_Pin */
  GPIO_InitStruct.Pin = ECON_Pin;
  GPIO_InitStruct.Mode = GPIO_MODE_OUTPUT_PP;
  GPIO_InitStruct.Pull = GPIO_NOPULL;
  GPIO_InitStruct.Speed = GPIO_SPEED_FREQ_LOW;
  HAL_GPIO_Init(ECON_GPIO_Port, &GPIO_InitStruct);

  /*Configure GPIO pins : PROPANE_IN_Pin PETROL_IN_Pin */
  GPIO_InitStruct.Pin = PROPANE_IN_Pin|PETROL_IN_Pin;
  GPIO_InitStruct.Mode = GPIO_MODE_INPUT;
  GPIO_InitStruct.Pull = GPIO_PULLUP;
  HAL_GPIO_Init(GPIOB, &GPIO_InitStruct);

  GPIO_InitStruct.Pin = IGN_23_Pin|IGN_14_Pin;
  GPIO_InitStruct.Mode = GPIO_MODE_OUTPUT_PP;
  GPIO_InitStruct.Pull = GPIO_NOPULL;
  GPIO_InitStruct.Speed = GPIO_SPEED_FREQ_VERY_HIGH;
  HAL_GPIO_Init(GPIOB, &GPIO_InitStruct);

  /* EXTI interrupt init*/
  HAL_NVIC_SetPriority(EXTI15_10_IRQn, 2, 0);
  HAL_NVIC_EnableIRQ(EXTI15_10_IRQn);

}

void Error_Handler(void)
{
  __disable_irq();
  while (1)
  {
  }
}

/************************ (C) COPYRIGHT STMicroelectronics *****END OF FILE****/
